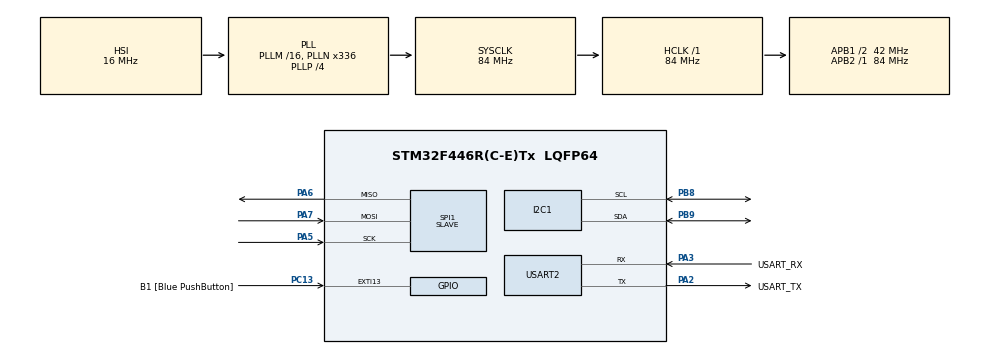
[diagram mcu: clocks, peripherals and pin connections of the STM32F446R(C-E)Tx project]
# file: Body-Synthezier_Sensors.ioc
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Mcu.Family=STM32F4
Dma.SPI1_TX.1.Priority=DMA_PRIORITY_LOW
PA6.Mode=Full_Duplex_Slave
PH0-OSC_IN.Signal=RCC_OSC_IN
RCC.CortexFreq_Value=84000000
SPI1.VirtualType=VM_SLAVE
Dma.SPI1_TX.1.FIFOMode=DMA_FIFOMODE_DISABLE
PA14.GPIO_Label=TCK
Dma.SPI1_TX.1.PeriphInc=DMA_PINC_DISABLE
PC13.GPIO_Label=B1 [Blue PushButton]
RCC.SYSCLKSource=RCC_SYSCLKSOURCE_PLLCLK
ProjectManager.StackSize=0x400
SPI1.CLKPolarity=SPI_POLARITY_HIGH
Dma.SPI1_RX.0.Direction=DMA_PERIPH_TO_MEMORY
SPI1.Direction=SPI_DIRECTION_2LINES
RCC.HCLKFreq_Value=84000000
RCC.APB2TimFreq_Value=84000000
NVIC.DMA2_Stream0_IRQn=true\:0\:0\:false\:false\:true\:false\:true
RCC.AHBFreq_Value=84000000
Dma.SPI1_TX.1.PeriphDataAlignment=DMA_PDATAALIGN_BYTE
RCC.HSE_VALUE=8000000
Dma.SPI1_RX.0.PeriphInc=DMA_PINC_DISABLE
Dma.SPI1_TX.1.Mode=DMA_CIRCULAR
RCC.FLatency-AdvancedSettings=FLASH_LATENCY_2
Mcu.Package=LQFP64
PB9.Signal=I2C1_SDA
PA6.Signal=SPI1_MISO
USART2.VirtualMode=VM_ASYNC
PA2.GPIO_Label=USART_TX
Dma.Request1=SPI1_TX
RCC.APB1TimFreq_Value=84000000
Dma.Request0=SPI1_RX
Dma.SPI1_TX.1.Instance=DMA2_Stream3
PA3.Signal=USART2_RX
PA5.Mode=Full_Duplex_Slave
PB3.GPIO_Label=SWO
Dma.SPI1_TX.1.MemInc=DMA_MINC_ENABLE
PA7.Mode=Full_Duplex_Slave
PC13.Signal=GPXTI13
Dma.SPI1_RX.0.Mode=DMA_CIRCULAR
RCC.APB1CLKDivider=RCC_HCLK_DIV2
PC14-OSC32_IN.Signal=RCC_OSC32_IN
Dma.SPI1_TX.1.Direction=DMA_MEMORY_TO_PERIPH
Dma.SPI1_RX.0.FIFOMode=DMA_FIFOMODE_DISABLE
PA13.Signal=SYS_JTMS-SWDIO
PA3.Mode=Asynchronous
Dma.SPI1_TX.1.MemDataAlignment=DMA_MDATAALIGN_BYTE
ProjectManager.TargetToolchain=STM32CubeIDE
I2C1.I2C_Mode=I2C_Fast
PB9.Mode=I2C
RCC.USBFreq_Value=168000000
NVIC.DMA2_Stream3_IRQn=true\:0\:0\:false\:false\:true\:false\:true
RCC.LSE_VALUE=32768
PC15-OSC32_OUT.Signal=RCC_OSC32_OUT
PA5.Signal=SPI1_SCK
board=NUCLEO-F446RE
RCC.VCOOutputFreq_Value=336000000
RCC.APB2Freq_Value=84000000
SPI1.Mode=SPI_MODE_SLAVE
Dma.SPI1_RX.0.Instance=DMA2_Stream0
Dma.SPI1_RX.0.PeriphDataAlignment=DMA_PDATAALIGN_BYTE
PH1-OSC_OUT.Signal=RCC_OSC_OUT
Dma.SPI1_RX.0.MemDataAlignment=DMA_MDATAALIGN_BYTE
Mcu.Name=STM32F446R(C-E)Tx
Dma.SPI1_RX.0.MemInc=DMA_MINC_ENABLE
PA13.GPIO_Label=TMS
PA2.Signal=USART2_TX
PB3.Signal=SYS_JTDO-SWO
RCC.SYSCLKFreq_VALUE=84000000
PC13.GPIO_ModeDefaultEXTI=GPIO_MODE_IT_FALLING
PA14.Signal=SYS_JTCK-SWCLK
ProjectManager.HeapSize=0x200
Dma.SPI1_RX.0.Priority=DMA_PRIORITY_LOW
RCC.HSI_VALUE=16000000
RCC.PLLP=RCC_PLLP_DIV4
NVIC.PriorityGroup=NVIC_PRIORITYGROUP_0
PB8.Mode=I2C
RCC.PLLN=336
PA2.Mode=Asynchronous
PB8.Signal=I2C1_SCL
RCC.APB1Freq_Value=42000000
PA3.GPIO_Label=USART_RX
PA7.Signal=SPI1_MOSI

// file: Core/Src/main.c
/* USER CODE BEGIN Header */
/**
 ******************************************************************************
 * @file           : main.c
 * @brief          : Main program body
 ******************************************************************************
 * @attention
 *
 * <h2><center>&copy; Copyright (c) 2021 STMicroelectronics.
 * All rights reserved.</center></h2>
 *
 * This software component is licensed by ST under BSD 3-Clause license,
 * the "License"; You may not use this file except in compliance with the
 * License. You may obtain a copy of the License at:
 *                        opensource.org/licenses/BSD-3-Clause
 *
 ******************************************************************************
 */
/* USER CODE END Header */
#include "main.h"

I2C_HandleTypeDef hi2c1;

SPI_HandleTypeDef hspi1;
DMA_HandleTypeDef hdma_spi1_rx;
DMA_HandleTypeDef hdma_spi1_tx;

UART_HandleTypeDef huart2;

void SystemClock_Config(void);
static void MX_GPIO_Init(void);
static void MX_DMA_Init(void);
static void MX_SPI1_Init(void);
static void MX_USART2_UART_Init(void);
static void MX_I2C1_Init(void);

int main(void)
{

  /* MCU Configuration--------------------------------------------------------*/

  /* Reset of all peripherals, Initializes the Flash interface and the Systick. */
  HAL_Init();

  /* Configure the system clock */
  SystemClock_Config();

  /* Initialize all configured peripherals */
  MX_GPIO_Init();
  MX_DMA_Init();
  MX_SPI1_Init();
  MX_USART2_UART_Init();
  MX_I2C1_Init();
  /* USER CODE BEGIN 2 */
	printf("***Bodysythesizer Sensor Board***\r\n");
	uint8_t initError_counter = 0;
	bool led_off = true;

	for (int i =0;i<BUFFERSIZE;i++){
		pTxData[i] = 0;
		pRxData[i] = 0;
	}
	//Power up Gyro
	HAL_GPIO_WritePin(MPU6050_Power_GPIO_Port, MPU6050_Power_Pin,SET );
	HAL_Delay(10);

	//Gyros Init
	MPU6050_Data gyro_data;
	//	 MPU6050_STATUS gyro_status;
	while((initError_counter < 5) && MPU6050_init(&hi2c1, &gyro_data, MPU6050_ACCL_8G, MPU6050_GYRO_2000deg, MPU6050_SampleRate_2KHz != MPU6050_Status_OK)){
		initError_counter++;
		printf("MPU6050 Init Error\r\n");
		if (initError_counter == 3){
			printf("restart MPU6050\r\n");
			HAL_GPIO_WritePin(MPU6050_Power_GPIO_Port, MPU6050_Power_Pin,RESET );
			HAL_Delay(10);
			HAL_GPIO_WritePin(MPU6050_Power_GPIO_Port, MPU6050_Power_Pin,SET );
			HAL_Delay(10);
		}
	}
	if (initError_counter < 5){
		printf("MPU6050 Init complete\r\n");
		if ( MPU6050_Calibrate(&gyro_data) == MPU6050_Read_OK){
			printf("MPU6050 calibrated\r\n");
			SyncBuffer.gyro_initilized =true;
		}
		else{
			printf("MPU6050 calibration failed\r\n");
			SyncBuffer.gyro_initilized = false;
		}
	}
	else {
		SyncBuffer.gyro_initilized = false;
	}

  /* USER CODE END 2 */

  /* Infinite loop */
  /* USER CODE BEGIN WHILE */

	HAL_SPI_TransmitReceive_DMA(&hspi1, pTxData, pRxData, BUFFERSIZE);
	while (1)
	{
		if(SyncBuffer.gyro_initilized == true){
			//			MPU6050_Display_Data();
			SyncBuffer.tilt_detecded  = MPU6050_detectTilt();
			SyncBuffer.UD_detecded  = MPU6050_Detect_MovementHIGH_DOWN();
			SyncBuffer.RL_detecded = MPU6050_Detect_MovementRIGHT_LEFT();

		}

		//write into SPI buffer
		__disable_irq();
		memcpy((void*)pTxData,(void*)&SyncBuffer, BUFFERSIZE);
		__enable_irq();

		//switch LED
		switch (SyncBuffer.tilt_detecded) {
		case TILT_RIGHT:
			HAL_GPIO_WritePin(LED_TILT_RIGHT_GPIO_Port, LED_TILT_RIGHT_Pin,SET );
			led_off = false;
			break;
		case TILT_RIGHT_S:
			HAL_GPIO_WritePin(LED_TILT_RIGHT_GPIO_Port, LED_TILT_RIGHT_Pin,SET );
			HAL_GPIO_WritePin(LED_STRONG_TILT_RIGHT_GPIO_Port, LED_STRONG_TILT_RIGHT_Pin,SET );
			led_off = false;
			break;
		case TILT_LEFT:
			HAL_GPIO_WritePin(LED_TILT_LEFT_GPIO_Port, LED_TILT_LEFT_Pin,SET );
			led_off = false;
			break;
		case TILT_LEFT_S:
			HAL_GPIO_WritePin(LED_TILT_LEFT_GPIO_Port, LED_TILT_LEFT_Pin,SET );
			HAL_GPIO_WritePin(LED_STRONG_TILT_LEFT_GPIO_Port, LED_STRONG_TILT_LEFT_Pin,SET );
			led_off = false;
			break;
		case TILT_FRONT:
			HAL_GPIO_WritePin(LED_TILT_FRONT_GPIO_Port, LED_TILT_FRONT_Pin,SET );
			led_off = false;
			break;
		case TILT_FRONT_S:
			HAL_GPIO_WritePin(LED_TILT_FRONT_GPIO_Port, LED_TILT_FRONT_Pin,SET );
			HAL_GPIO_WritePin(LED_STRONG_TILT_FRONT_GPIO_Port, LED_STRONG_TILT_FRONT_Pin,SET );
			led_off = false;
			break;
		case TILT_BACK:
			HAL_GPIO_WritePin(LED_TILT_BACK_GPIO_Port, LED_TILT_BACK_Pin,SET );
			led_off = false;
			break;
		case TILT_BACK_S:
			HAL_GPIO_WritePin(LED_TILT_BACK_GPIO_Port, LED_TILT_BACK_Pin,SET );
			HAL_GPIO_WritePin(LED_STRONG_TILT_BACK_GPIO_Port, LED_STRONG_TILT_BACK_Pin,SET );
			led_off = false;
			break;
		default:
			if (!led_off) {
				HAL_GPIO_WritePin(LED_TILT_LEFT_GPIO_Port, LED_TILT_LEFT_Pin,RESET );
				HAL_GPIO_WritePin(LED_STRONG_TILT_LEFT_GPIO_Port, LED_STRONG_TILT_LEFT_Pin,RESET );
				HAL_GPIO_WritePin(LED_TILT_FRONT_GPIO_Port, LED_TILT_FRONT_Pin,RESET );
				HAL_GPIO_WritePin(LED_STRONG_TILT_FRONT_GPIO_Port, LED_STRONG_TILT_FRONT_Pin,RESET );
				HAL_GPIO_WritePin(LED_TILT_BACK_GPIO_Port, LED_TILT_BACK_Pin,RESET );
				HAL_GPIO_WritePin(LED_STRONG_TILT_BACK_GPIO_Port, LED_STRONG_TILT_BACK_Pin,RESET );
				HAL_GPIO_WritePin(LED_TILT_RIGHT_GPIO_Port, LED_TILT_RIGHT_Pin,RESET );
				HAL_GPIO_WritePin(LED_STRONG_TILT_RIGHT_GPIO_Port, LED_STRONG_TILT_RIGHT_Pin,RESET );
				led_off = true;
			}

			break;
		}
		//	HAL_Delay(10);
    /* USER CODE END WHILE */

	}
}

void SystemClock_Config(void)
{
  RCC_OscInitTypeDef RCC_OscInitStruct = {0};
  RCC_ClkInitTypeDef RCC_ClkInitStruct = {0};

  /** Configure the main internal regulator output voltage
  */
  __HAL_RCC_PWR_CLK_ENABLE();
  __HAL_PWR_VOLTAGESCALING_CONFIG(PWR_REGULATOR_VOLTAGE_SCALE3);
  /** Initializes the RCC Oscillators according to the specified parameters
  * in the RCC_OscInitTypeDef structure.
  */
  RCC_OscInitStruct.OscillatorType = RCC_OSCILLATORTYPE_HSI;
  RCC_OscInitStruct.HSIState = RCC_HSI_ON;
  RCC_OscInitStruct.HSICalibrationValue = RCC_HSICALIBRATION_DEFAULT;
  RCC_OscInitStruct.PLL.PLLState = RCC_PLL_ON;
  RCC_OscInitStruct.PLL.PLLSource = RCC_PLLSOURCE_HSI;
  RCC_OscInitStruct.PLL.PLLM = 16;
  RCC_OscInitStruct.PLL.PLLN = 336;
  RCC_OscInitStruct.PLL.PLLP = RCC_PLLP_DIV4;
  RCC_OscInitStruct.PLL.PLLQ = 2;
  RCC_OscInitStruct.PLL.PLLR = 2;
  if (HAL_RCC_OscConfig(&RCC_OscInitStruct) != HAL_OK)
  {
    Error_Handler();
  }
  /** Initializes the CPU, AHB and APB buses clocks
  */
  RCC_ClkInitStruct.ClockType = RCC_CLOCKTYPE_HCLK|RCC_CLOCKTYPE_SYSCLK
                              |RCC_CLOCKTYPE_PCLK1|RCC_CLOCKTYPE_PCLK2;
  RCC_ClkInitStruct.SYSCLKSource = RCC_SYSCLKSOURCE_PLLCLK;
  RCC_ClkInitStruct.AHBCLKDivider = RCC_SYSCLK_DIV1;
  RCC_ClkInitStruct.APB1CLKDivider = RCC_HCLK_DIV2;
  RCC_ClkInitStruct.APB2CLKDivider = RCC_HCLK_DIV1;

  if (HAL_RCC_ClockConfig(&RCC_ClkInitStruct, FLASH_LATENCY_2) != HAL_OK)
  {
    Error_Handler();
  }
}

static void MX_I2C1_Init(void)
{

  hi2c1.Instance = I2C1;
  hi2c1.Init.ClockSpeed = 400000;
  hi2c1.Init.DutyCycle = I2C_DUTYCYCLE_2;
  hi2c1.Init.OwnAddress1 = 0;
  hi2c1.Init.AddressingMode = I2C_ADDRESSINGMODE_7BIT;
  hi2c1.Init.DualAddressMode = I2C_DUALADDRESS_DISABLE;
  hi2c1.Init.OwnAddress2 = 0;
  hi2c1.Init.GeneralCallMode = I2C_GENERALCALL_DISABLE;
  hi2c1.Init.NoStretchMode = I2C_NOSTRETCH_DISABLE;
  if (HAL_I2C_Init(&hi2c1) != HAL_OK)
  {
    Error_Handler();
  }

}

static void MX_SPI1_Init(void)
{

  /* SPI1 parameter configuration*/
  hspi1.Instance = SPI1;
  hspi1.Init.Mode = SPI_MODE_SLAVE;
  hspi1.Init.Direction = SPI_DIRECTION_2LINES;
  hspi1.Init.DataSize = SPI_DATASIZE_8BIT;
  hspi1.Init.CLKPolarity = SPI_POLARITY_HIGH;
  hspi1.Init.CLKPhase = SPI_PHASE_1EDGE;
  hspi1.Init.NSS = SPI_NSS_SOFT;
  hspi1.Init.FirstBit = SPI_FIRSTBIT_MSB;
  hspi1.Init.TIMode = SPI_TIMODE_DISABLE;
  hspi1.Init.CRCCalculation = SPI_CRCCALCULATION_DISABLE;
  hspi1.Init.CRCPolynomial = 10;
  if (HAL_SPI_Init(&hspi1) != HAL_OK)
  {
    Error_Handler();
  }

}

static void MX_USART2_UART_Init(void)
{

  huart2.Instance = USART2;
  huart2.Init.BaudRate = 115200;
  huart2.Init.WordLength = UART_WORDLENGTH_8B;
  huart2.Init.StopBits = UART_STOPBITS_1;
  huart2.Init.Parity = UART_PARITY_NONE;
  huart2.Init.Mode = UART_MODE_TX_RX;
  huart2.Init.HwFlowCtl = UART_HWCONTROL_NONE;
  huart2.Init.OverSampling = UART_OVERSAMPLING_16;
  if (HAL_UART_Init(&huart2) != HAL_OK)
  {
    Error_Handler();
  }

}

static void MX_DMA_Init(void)
{

  /* DMA controller clock enable */
  __HAL_RCC_DMA2_CLK_ENABLE();

  /* DMA interrupt init */
  /* DMA2_Stream0_IRQn interrupt configuration */
  HAL_NVIC_SetPriority(DMA2_Stream0_IRQn, 0, 0);
  HAL_NVIC_EnableIRQ(DMA2_Stream0_IRQn);
  /* DMA2_Stream3_IRQn interrupt configuration */
  HAL_NVIC_SetPriority(DMA2_Stream3_IRQn, 0, 0);
  HAL_NVIC_EnableIRQ(DMA2_Stream3_IRQn);

}

static void MX_GPIO_Init(void)
{
  GPIO_InitTypeDef GPIO_InitStruct = {0};

  /* GPIO Ports Clock Enable */
  __HAL_RCC_GPIOC_CLK_ENABLE();
  __HAL_RCC_GPIOH_CLK_ENABLE();
  __HAL_RCC_GPIOA_CLK_ENABLE();
  __HAL_RCC_GPIOB_CLK_ENABLE();

  /*Configure GPIO pin Output Level */
  HAL_GPIO_WritePin(GPIOC, LED_TILT_BACK_Pin|MPU6050_Power_Pin, GPIO_PIN_RESET);

  /*Configure GPIO pin Output Level */
  HAL_GPIO_WritePin(GPIOB, LED_STRONG_TILT_RIGHT_Pin|LED_STRONG_TILT_BACK_Pin|LED_TILT_FRONT_Pin|LED_TILT_LEFT_Pin
                          |LED_STRONG_TILT_LEFT_Pin, GPIO_PIN_RESET);

  /*Configure GPIO pin Output Level */
  HAL_GPIO_WritePin(GPIOA, LED_TILT_RIGHT_Pin|LED_STRONG_TILT_FRONT_Pin, GPIO_PIN_RESET);

  /*Configure GPIO pin : B1_Pin */
  GPIO_InitStruct.Pin = B1_Pin;
  GPIO_InitStruct.Mode = GPIO_MODE_IT_FALLING;
  GPIO_InitStruct.Pull = GPIO_NOPULL;
  HAL_GPIO_Init(B1_GPIO_Port, &GPIO_InitStruct);

  /*Configure GPIO pins : LED_TILT_BACK_Pin MPU6050_Power_Pin */
  GPIO_InitStruct.Pin = LED_TILT_BACK_Pin|MPU6050_Power_Pin;
  GPIO_InitStruct.Mode = GPIO_MODE_OUTPUT_PP;
  GPIO_InitStruct.Pull = GPIO_NOPULL;
  GPIO_InitStruct.Speed = GPIO_SPEED_FREQ_LOW;
  HAL_GPIO_Init(GPIOC, &GPIO_InitStruct);

  /*Configure GPIO pins : LED_STRONG_TILT_RIGHT_Pin LED_STRONG_TILT_BACK_Pin LED_TILT_FRONT_Pin LED_TILT_LEFT_Pin
                           LED_STRONG_TILT_LEFT_Pin */
  GPIO_InitStruct.Pin = LED_STRONG_TILT_RIGHT_Pin|LED_STRONG_TILT_BACK_Pin|LED_TILT_FRONT_Pin|LED_TILT_LEFT_Pin
                          |LED_STRONG_TILT_LEFT_Pin;
  GPIO_InitStruct.Mode = GPIO_MODE_OUTPUT_PP;
  GPIO_InitStruct.Pull = GPIO_NOPULL;
  GPIO_InitStruct.Speed = GPIO_SPEED_FREQ_LOW;
  HAL_GPIO_Init(GPIOB, &GPIO_InitStruct);

  /*Configure GPIO pins : LED_TILT_RIGHT_Pin LED_STRONG_TILT_FRONT_Pin */
  GPIO_InitStruct.Pin = LED_TILT_RIGHT_Pin|LED_STRONG_TILT_FRONT_Pin;
  GPIO_InitStruct.Mode = GPIO_MODE_OUTPUT_PP;
  GPIO_InitStruct.Pull = GPIO_NOPULL;
  GPIO_InitStruct.Speed = GPIO_SPEED_FREQ_LOW;
  HAL_GPIO_Init(GPIOA, &GPIO_InitStruct);

}

/* USER CODE BEGIN 4 */
//printf()
int __io_putchar(int ch)
{
	uint8_t c[1];
	c[0] = ch & 0x00FF;
	HAL_UART_Transmit(&huart2, &*c, 1, 10);
	return ch;
}

int _write(int file,char *ptr, int len)
{
	int DataIdx;
	for(DataIdx= 0; DataIdx< len; DataIdx++)
	{
		__io_putchar(*ptr++);
	}
	return len;
}
//printf() end
/* USER CODE END 4 */

void Error_Handler(void)
{
	__disable_irq();
	while (1)
	{
	}
}

/************************ (C) COPYRIGHT STMicroelectronics *****END OF FILE****/
